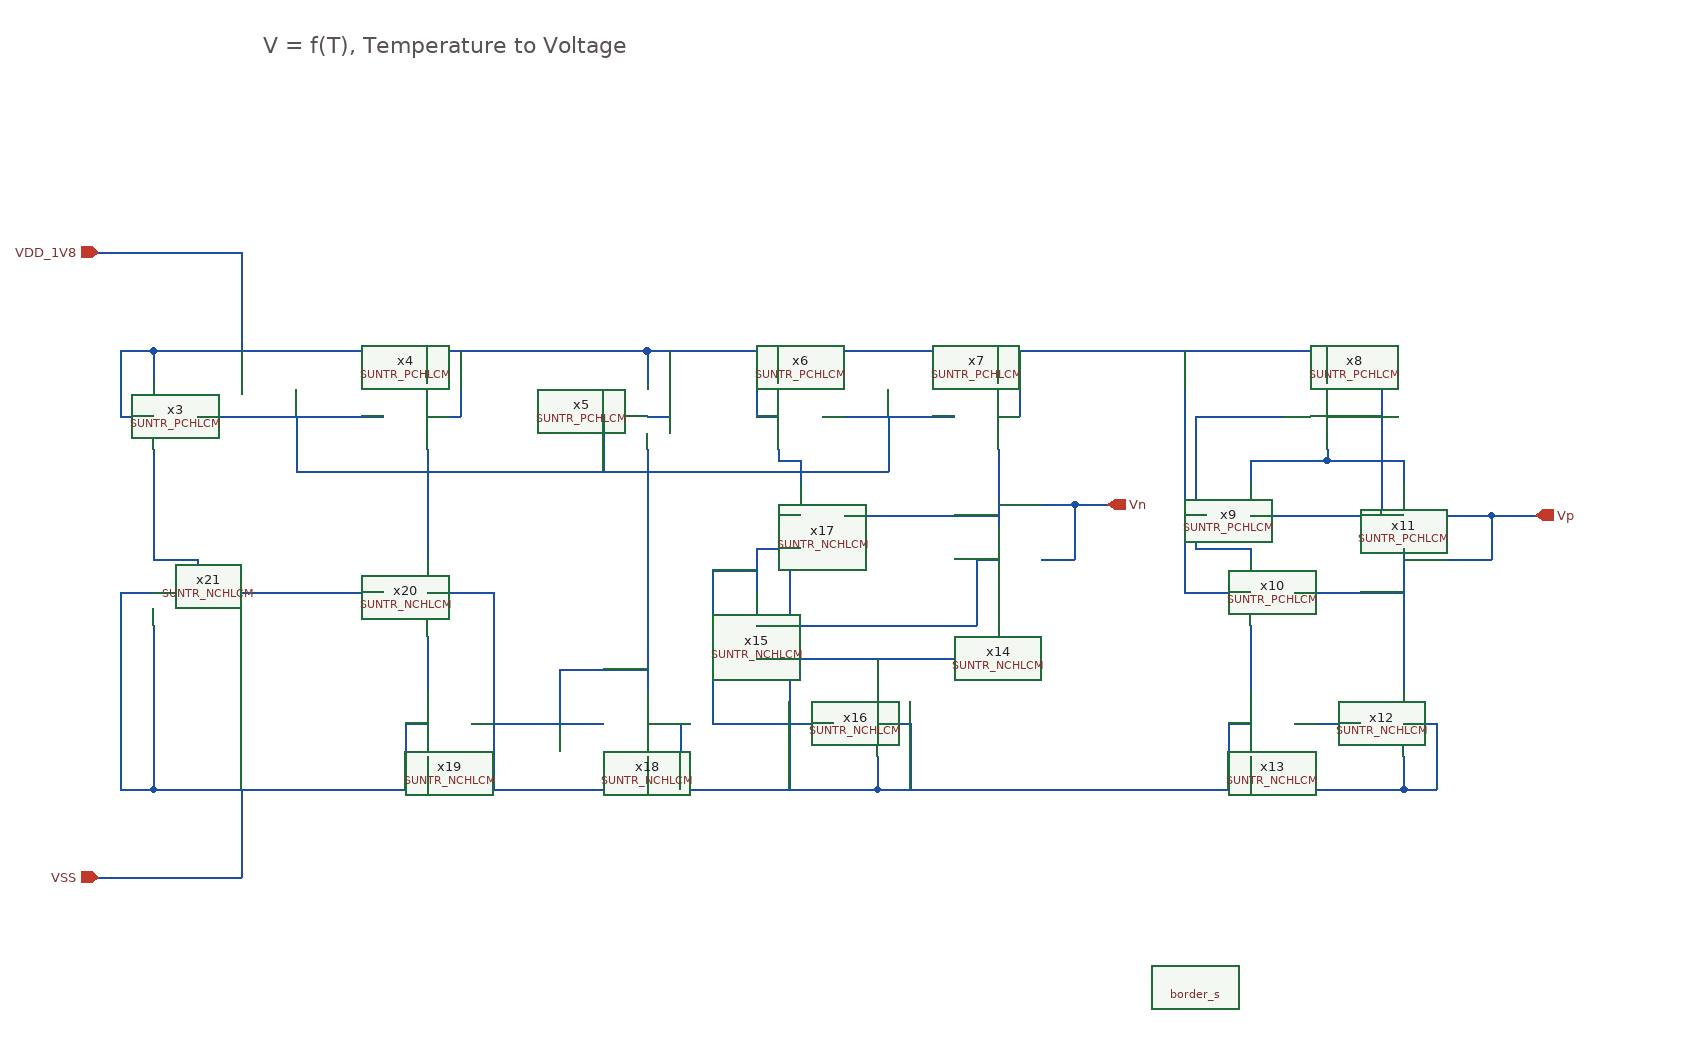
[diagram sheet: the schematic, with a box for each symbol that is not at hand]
v {xschem version=3.4.4 file_version=1.2
}
G {}
K {}
V {}
S {}
E {}
T {V = f(T), Temperature to Voltage} 400 -1040 0 0 1 1 {}
N 300 -750 300 -720 {
lab=VDD_1V8}
N 300 -750 550 -750 {
lab=VDD_1V8}
N 550 -750 550 -720 {
lab=VDD_1V8}
N 550 -750 740 -750 {
lab=VDD_1V8}
N 340 -690 510 -690 {
lab=#net1}
N 550 -490 550 -440 {
lab=#net2}
N 590 -410 710 -410 {
lab=#net3}
N 670 -460 670 -410 {
lab=#net3}
N 670 -460 750 -460 {
lab=#net3}
N 740 -750 750 -750 {
lab=VDD_1V8}
N 750 -750 750 -720 {
lab=VDD_1V8}
N 430 -690 430 -640 {
lab=#net1}
N 430 -640 660 -640 {
lab=#net1}
N 1070 -530 1070 -490 {
lab=#net4}
N 1070 -660 1070 -590 {
lab=Vn}
N 870 -750 870 -720 {
lab=VDD_1V8}
N 750 -750 870 -750 {
lab=VDD_1V8}
N 750 -750 870 -750 {
lab=VDD_1V8}
N 870 -750 1070 -750 {
lab=VDD_1V8}
N 1070 -750 1070 -720 {
lab=VDD_1V8}
N 1070 -610 1140 -610 {
lab=Vn}
N 1140 -610 1140 -560 {
lab=Vn}
N 1110 -560 1140 -560 {
lab=Vn}
N 1140 -610 1170 -610 {
lab=Vn}
N 1440 -570 1440 -440 {
lab=Vp}
N 1440 -650 1440 -630 {
lab=#net5}
N 1370 -650 1440 -650 {
lab=#net5}
N 1370 -660 1370 -650 {
lab=#net5}
N 1300 -650 1370 -650 {
lab=#net5}
N 1300 -650 1300 -630 {
lab=#net5}
N 1300 -570 1300 -560 {
lab=#net6}
N 1340 -530 1440 -530 {
lab=Vp}
N 1340 -410 1400 -410 {
lab=#net7}
N 1370 -750 1370 -720 {
lab=VDD_1V8}
N 1070 -750 1370 -750 {
lab=VDD_1V8}
N 1250 -690 1330 -690 {
lab=#net6}
N 1250 -690 1250 -600 {
lab=#net6}
N 1250 -600 1260 -600 {
lab=#net6}
N 1250 -600 1250 -570 {
lab=#net6}
N 1250 -570 1300 -570 {
lab=#net6}
N 1480 -600 1520 -600 {
lab=Vp}
N 1520 -600 1520 -560 {
lab=Vp}
N 1440 -560 1520 -560 {
lab=Vp}
N 1520 -600 1560 -600 {
lab=Vp}
N 1440 -380 1440 -350 {
lab=VSS}
N 1300 -350 1440 -350 {
lab=VSS}
N 1300 -380 1300 -350 {
lab=VSS}
N 960 -350 1300 -350 {
lab=VSS}
N 960 -380 960 -350 {
lab=VSS}
N 750 -350 960 -350 {
lab=VSS}
N 750 -380 750 -350 {
lab=VSS}
N 550 -350 750 -350 {
lab=VSS}
N 550 -380 550 -350 {
lab=VSS}
N 300 -350 550 -350 {
lab=VSS}
N 300 -500 300 -350 {
lab=VSS}
N 250 -270 380 -270 {
lab=VSS}
N 380 -350 380 -270 {
lab=VSS}
N 250 -840 380 -840 {
lab=VDD_1V8}
N 380 -840 380 -750 {
lab=VDD_1V8}
N 750 -660 750 -440 {
lab=#net3}
N 660 -640 970 -640 {
lab=#net1}
N 970 -690 970 -640 {
lab=#net1}
N 910 -690 1030 -690 {
lab=#net1}
N 1300 -500 1300 -440 {
lab=#net8}
N 710 -690 710 -640 {
lab=#net1}
N 300 -660 300 -560 {
lab=#net9}
N 300 -560 340 -560 {
lab=#net9}
N 340 -560 340 -530 {
lab=#net9}
N 340 -530 510 -530 {
lab=#net9}
N 890 -650 890 -630 {
lab=#net10}
N 870 -650 890 -650 {
lab=#net10}
N 870 -660 870 -650 {
lab=#net10}
N 930 -600 1070 -600 {
lab=Vn}
N 550 -690 580 -690 {
lab=VDD_1V8}
N 580 -750 580 -690 {
lab=VDD_1V8}
N 750 -690 770 -690 {
lab=VDD_1V8}
N 770 -750 770 -690 {
lab=VDD_1V8}
N 850 -690 870 -690 {
lab=VDD_1V8}
N 850 -750 850 -690 {
lab=VDD_1V8}
N 1070 -690 1090 -690 {
lab=VDD_1V8}
N 1090 -750 1090 -690 {
lab=VDD_1V8}
N 1240 -530 1300 -530 {
lab=VDD_1V8}
N 1240 -750 1240 -530 {
lab=VDD_1V8}
N 1300 -600 1440 -600 {
lab=VDD_1V8}
N 1420 -750 1420 -600 {
lab=VDD_1V8}
N 1370 -750 1420 -750 {
lab=VDD_1V8}
N 1370 -690 1420 -690 {
lab=VDD_1V8}
N 270 -690 300 -690 {
lab=VDD_1V8}
N 270 -750 270 -690 {
lab=VDD_1V8}
N 270 -750 300 -750 {
lab=VDD_1V8}
N 270 -530 300 -530 {
lab=VSS}
N 270 -530 270 -350 {
lab=VSS}
N 270 -350 300 -350 {
lab=VSS}
N 550 -530 610 -530 {
lab=VSS}
N 610 -530 610 -350 {
lab=VSS}
N 530 -410 550 -410 {
lab=VSS}
N 530 -410 530 -350 {
lab=VSS}
N 750 -410 780 -410 {
lab=VSS}
N 780 -410 780 -350 {
lab=VSS}
N 880 -600 890 -600 {
lab=VSS}
N 880 -600 880 -350 {
lab=VSS}
N 850 -470 1070 -470 {
lab=#net4}
N 1070 -530 1070 -470 {
lab=#net4}
N 960 -470 960 -440 {
lab=#net4}
N 850 -570 890 -570 {
lab=#net11}
N 850 -570 850 -530 {
lab=#net11}
N 810 -550 810 -500 {
lab=#net11}
N 810 -550 850 -550 {
lab=#net11}
N 810 -500 810 -410 {
lab=#net11}
N 810 -410 920 -410 {
lab=#net11}
N 850 -500 880 -500 {
lab=VSS}
N 1050 -560 1070 -560 {
lab=VSS}
N 1050 -560 1050 -500 {
lab=VSS}
N 880 -500 1050 -500 {
lab=VSS}
N 960 -410 990 -410 {
lab=VSS}
N 990 -410 990 -350 {
lab=VSS}
N 1280 -410 1300 -410 {
lab=VSS}
N 1280 -410 1280 -350 {
lab=VSS}
N 1440 -410 1470 -410 {
lab=VSS}
N 1470 -410 1470 -350 {
lab=VSS}
N 1440 -350 1470 -350 {
lab=VSS}
N 550 -660 550 -640 {
lab=#net1}
N 550 -640 550 -560 {
lab=#net1}
C {cborder/border_s.sym} 1250 -170 0 0 {
user="wulff"
company="wulff"}
C {devices/ipin.sym} 250 -840 0 0 {name=p1 lab=VDD_1V8
}
C {devices/ipin.sym} 250 -270 0 0 {name=p3 lab=VSS}
C {devices/opin.sym} 1170 -610 0 0 {name=p4 lab=Vn}
C {devices/opin.sym} 1560 -600 0 0 {name=p5 lab=Vp}
C {SUN_TR_SKY130NM/SUNTR_PCHLCM.sym} 340 -690 0 1 {name=x3 }
C {SUN_TR_SKY130NM/SUNTR_PCHLCM.sym} 510 -690 0 0 {name=x4 }
C {SUN_TR_SKY130NM/SUNTR_PCHLCM.sym} 710 -690 0 0 {name=x5 }
C {SUN_TR_SKY130NM/SUNTR_PCHLCM.sym} 910 -690 0 1 {name=x6 }
C {SUN_TR_SKY130NM/SUNTR_PCHLCM.sym} 1030 -690 0 0 {name=x7 }
C {SUN_TR_SKY130NM/SUNTR_PCHLCM.sym} 1330 -690 0 0 {name=x8 }
C {SUN_TR_SKY130NM/SUNTR_PCHLCM.sym} 1260 -600 0 0 {name=x9 }
C {SUN_TR_SKY130NM/SUNTR_PCHLCM.sym} 1340 -530 0 1 {name=x10 }
C {SUN_TR_SKY130NM/SUNTR_PCHLCM.sym} 1480 -600 0 1 {name=x11 }
C {SUN_TR_SKY130NM/SUNTR_NCHLCM.sym} 1400 -410 0 0 {name=x12 }
C {SUN_TR_SKY130NM/SUNTR_NCHLCM.sym} 1340 -410 0 1 {name=x13 }
C {SUN_TR_SKY130NM/SUNTR_NCHLCM.sym} 1110 -560 0 1 {name=x14 }
C {SUN_TR_SKY130NM/SUNTR_NCHLCM.sym} 810 -500 0 0 {name=x15 }
C {SUN_TR_SKY130NM/SUNTR_NCHLCM.sym} 920 -410 0 0 {name=x16 }
C {SUN_TR_SKY130NM/SUNTR_NCHLCM.sym} 930 -600 0 1 {name=x17 }
C {SUN_TR_SKY130NM/SUNTR_NCHLCM.sym} 710 -410 0 0 {name=x18 }
C {SUN_TR_SKY130NM/SUNTR_NCHLCM.sym} 590 -410 0 1 {name=x19 }
C {SUN_TR_SKY130NM/SUNTR_NCHLCM.sym} 510 -530 0 0 {name=x20 }
C {SUN_TR_SKY130NM/SUNTR_NCHLCM.sym} 340 -530 0 1 {name=x21 }
